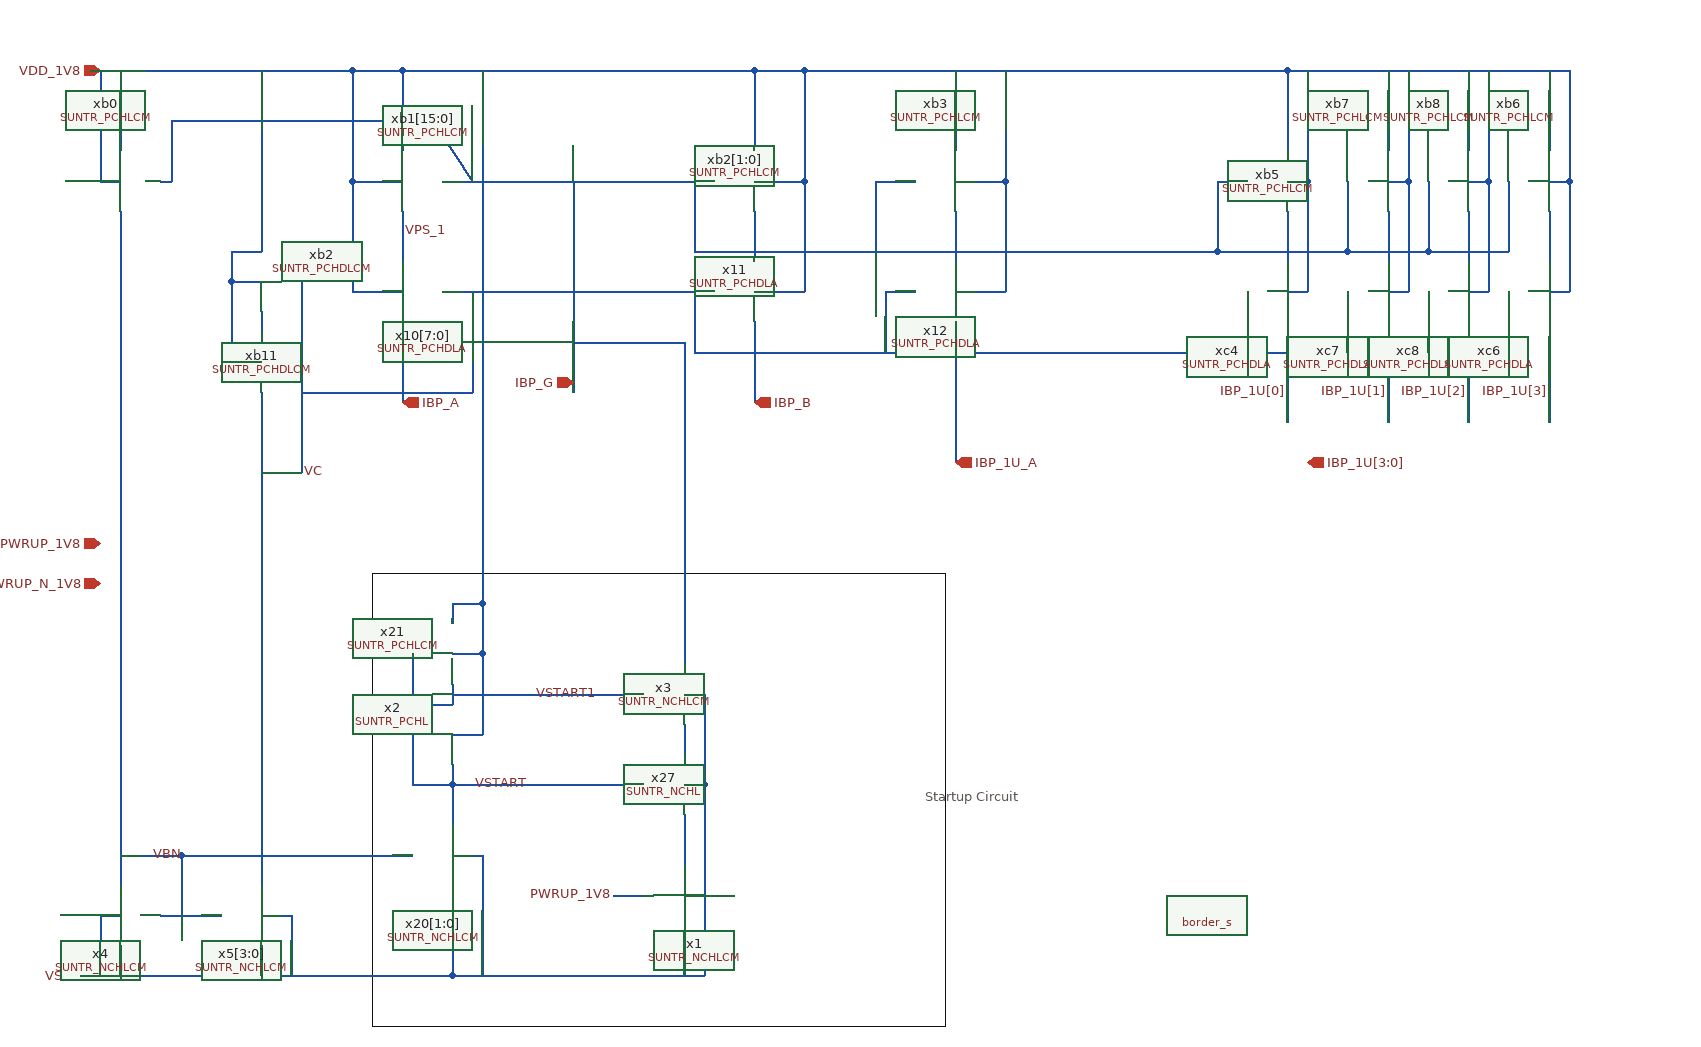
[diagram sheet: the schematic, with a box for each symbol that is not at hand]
v {xschem version=3.1.0 file_version=1.2
}
G {}
K {}
V {}
S {}
E {}
L 3 -320 -340 250 -340 {}
L 3 -320 -340 -320 110 {}
L 3 250 -340 250 110 {}
L 3 -320 110 250 110 {}
T {Startup Circuit} 230 -130 0 1 0.4 0.4 {}
N -340 -730 -290 -730 {
lab=VDD_1V8}
N -340 -760 -340 -730 {
lab=VDD_1V8}
N -340 -840 -340 -760 {
lab=VDD_1V8}
N -340 -840 -290 -840 {
lab=VDD_1V8}
N -290 -840 -290 -760 {
lab=VDD_1V8}
N -290 -840 60 -840 {
lab=VDD_1V8}
N 60 -840 60 -760 {
lab=VDD_1V8}
N -250 -730 20 -730 {
lab=IBP_G}
N -600 -840 -340 -840 {
lab=VDD_1V8}
N -610 60 -370 60 {
lab=VSS}
N 60 -730 110 -730 {
lab=VDD_1V8}
N 110 -840 110 -730 {
lab=VDD_1V8}
N 60 -840 110 -840 {
lab=VDD_1V8}
N 590 -840 590 -760 {
lab=VDD_1V8}
N 110 -840 590 -840 {
lab=VDD_1V8}
N 590 -840 630 -840 {
lab=VDD_1V8}
N 520 -730 550 -730 {
lab=IBP_G}
N 520 -730 520 -660 {
lab=IBP_G}
N 0 -660 520 -660 {
lab=IBP_G}
N 0 -730 0 -660 {
lab=IBP_G}
N 260 -730 310 -730 {
lab=VDD_1V8}
N 310 -840 310 -730 {
lab=VDD_1V8}
N 260 -840 260 -760 {
lab=VDD_1V8}
N 180 -730 220 -730 {
lab=IBP_G}
N 180 -730 180 -660 {
lab=IBP_G}
N -570 -840 -570 -760 {
lab=VDD_1V8}
N -590 -730 -570 -730 {
lab=VDD_1V8}
N -590 -840 -590 -730 {
lab=VDD_1V8}
N -460 -630 -430 -630 {
lab=VDD_1V8}
N -460 -660 -460 -630 {
lab=VDD_1V8}
N -460 -660 -430 -660 {
lab=VDD_1V8}
N -430 -840 -430 -660 {
lab=VDD_1V8}
N -260 -790 -220 -730 {
lab=IBP_G}
N -520 -790 -260 -790 {
lab=IBP_G}
N -520 -790 -520 -730 {
lab=IBP_G}
N -530 -730 -520 -730 {
lab=IBP_G}
N -570 -700 -570 -30 {
lab=VBN}
N -590 -0 -570 -0 {
lab=VSS}
N -590 -0 -590 60 {
lab=VSS}
N -570 30 -570 60 {
lab=VSS}
N -430 30 -430 60 {
lab=VSS}
N -430 0 -400 0 {
lab=VSS}
N -400 0 -400 60 {
lab=VSS}
N -530 0 -470 0 {
lab=VBN}
N -430 -600 -430 -580 {
lab=#net1}
N -430 -450 -430 -30 {
lab=VC}
N -430 -440 -390 -440 {
lab=VC}
N -390 -470 -390 -440 {
lab=VC}
N -390 -550 -390 -470 {
lab=VC}
N -390 -630 -390 -550 {
lab=VC}
N -290 -700 -290 -650 {
lab=VPS_1}
N -340 -620 -290 -620 {
lab=VDD_1V8}
N -340 -730 -340 -620 {
lab=VDD_1V8}
N 60 -700 60 -650 {
lab=#net2}
N 60 -620 110 -620 {
lab=VDD_1V8}
N 110 -730 110 -620 {
lab=VDD_1V8}
N 260 -700 260 -650 {
lab=#net3}
N 260 -620 310 -620 {
lab=VDD_1V8}
N 310 -730 310 -620 {
lab=VDD_1V8}
N 260 -590 260 -570 {
lab=IBP_1U_A}
N 330 -560 390 -560 {
lab=VC}
N 390 -560 550 -560 {
lab=VC}
N 550 -620 550 -560 {
lab=VC}
N -10 -620 20 -620 {
lab=VC}
N -390 -520 -310 -520 {
lab=VC}
N -570 -60 -510 -60 {
lab=VBN}
N -510 -60 -510 0 {
lab=VBN}
N -430 -460 -430 -450 {
lab=VC}
N 590 -700 590 -650 {
lab=#net4}
N 590 -730 610 -730 {
lab=VDD_1V8}
N 610 -840 610 -730 {
lab=VDD_1V8}
N 610 -730 610 -620 {
lab=VDD_1V8}
N 590 -620 610 -620 {
lab=VDD_1V8}
N 690 -840 690 -760 {
lab=VDD_1V8}
N 690 -700 690 -650 {
lab=#net5}
N 690 -730 710 -730 {
lab=VDD_1V8}
N 710 -840 710 -730 {
lab=VDD_1V8}
N 710 -730 710 -620 {
lab=VDD_1V8}
N 690 -620 710 -620 {
lab=VDD_1V8}
N 770 -840 770 -760 {
lab=VDD_1V8}
N 770 -700 770 -650 {
lab=#net6}
N 770 -730 790 -730 {
lab=VDD_1V8}
N 790 -840 790 -730 {
lab=VDD_1V8}
N 790 -730 790 -620 {
lab=VDD_1V8}
N 770 -620 790 -620 {
lab=VDD_1V8}
N 850 -840 850 -760 {
lab=VDD_1V8}
N 850 -700 850 -650 {
lab=#net7}
N 850 -730 870 -730 {
lab=VDD_1V8}
N 870 -840 870 -730 {
lab=VDD_1V8}
N 870 -730 870 -620 {
lab=VDD_1V8}
N 850 -620 870 -620 {
lab=VDD_1V8}
N 630 -840 870 -840 {
lab=VDD_1V8}
N 650 -730 650 -670 {
lab=IBP_G}
N 650 -670 650 -660 {
lab=IBP_G}
N 520 -660 650 -660 {
lab=IBP_G}
N 650 -660 730 -660 {
lab=IBP_G}
N 730 -730 730 -660 {
lab=IBP_G}
N 730 -660 810 -660 {
lab=IBP_G}
N 810 -730 810 -660 {
lab=IBP_G}
N 590 -590 590 -490 {
lab=IBP_1U[0]}
N 690 -590 690 -490 {
lab=IBP_1U[1]}
N 770 -590 770 -490 {
lab=IBP_1U[2]}
N 850 -590 850 -490 {
lab=IBP_1U[3]}
N 550 -560 810 -560 {
lab=VC}
N 810 -620 810 -560 {
lab=VC}
N 730 -620 730 -560 {
lab=VC}
N 650 -620 650 -560 {
lab=VC}
N -230 -620 -10 -620 {
lab=VC}
N 260 -570 260 -450 {
lab=IBP_1U_A}
N -290 -590 -290 -510 {
lab=IBP_A}
N 60 -590 60 -510 {
lab=IBP_B}
N -120 -730 -120 -520 {
lab=IBP_G}
N 10 30 10 60 {
lab=VSS}
N -230 60 -40 60 {
lab=VSS}
N -40 60 10 60 {
lab=VSS}
N -240 -60 -210 -60 {
lab=VSS}
N -210 -60 -210 60 {
lab=VSS}
N -240 -30 -240 60 {
lab=VSS}
N -240 -260 -210 -260 {
lab=VDD_1V8}
N -210 -310 -210 -260 {
lab=VDD_1V8}
N -240 -310 -240 -290 {
lab=VDD_1V8}
N -240 -140 -240 -120 {
lab=VSTART}
N -240 -130 -200 -130 {
lab=VSTART}
N -10 -130 10 -130 {
lab=VSS}
N 10 -130 10 30 {
lab=VSS}
N -10 -190 -10 -160 {
lab=#net8}
N -200 -130 -50 -130 {
lab=VSTART}
N -10 -100 -10 -50 {
lab=#net9}
N -10 -20 10 -20 {
lab=VSS}
N -10 10 -10 60 {
lab=VSS}
N -80 -20 -50 -20 {
lab=PWRUP_1V8}
N -240 -310 -210 -310 {
lab=VDD_1V8}
N -280 -260 -280 -210 {
lab=VSTART1}
N -280 -210 -240 -210 {
lab=VSTART1}
N -240 -230 -240 -210 {
lab=VSTART1}
N -240 -180 -210 -180 {
lab=VDD_1V8}
N -210 -260 -210 -180 {
lab=VDD_1V8}
N -280 -180 -280 -130 {
lab=VSTART}
N -280 -130 -240 -130 {
lab=VSTART}
N -240 -150 -240 -130 {
lab=VSTART}
N -240 -140 -240 -130 {
lab=VSTART}
N -10 -220 10 -220 {
lab=VSS}
N 10 -220 10 -130 {
lab=VSS}
N -10 -260 -10 -250 {
lab=IBP_G}
N -160 -220 -50 -220 {
lab=VSTART1}
N -240 -220 -190 -220 {
lab=VSTART1}
N 0 -620 -0 -560 {
lab=VC}
N -0 -560 330 -560 {
lab=VC}
N -250 -620 -230 -620 {
lab=VC}
N -310 -520 -220 -520 {
lab=VC}
N -220 -620 -220 -520 {
lab=VC}
N -240 -120 -240 -90 {
lab=VSTART}
N -510 -60 -280 -60 {
lab=VBN}
N -240 60 -230 60 {
lab=VSS}
N -370 60 -240 60 {
lab=VSS}
N -210 -840 -210 -310 {
lab=VDD_1V8}
N -120 -570 -10 -570 {
lab=IBP_G}
N -10 -570 -10 -260 {
lab=IBP_G}
N -460 -550 -430 -550 {
lab=VDD_1V8}
N -460 -630 -460 -550 {
lab=VDD_1V8}
N -430 -520 -430 -460 {
lab=VC}
N -190 -220 -160 -220 {
lab=VSTART1}
N 190 -620 220 -620 {
lab=VC}
N 190 -620 190 -560 {
lab=VC}
C {cborder/border_s.sym} 510 0 0 0 {
user="Carsten Wulff"
company="Carsten Wulff Software"}
C {devices/ipin.sym} -590 -840 0 0 {name=p1 lab=VDD_1V8}
C {devices/ipin.sym} -600 60 0 0 {name=p2 lab=VSS}
C {devices/opin.sym} 610 -450 1 0 {name=p8 lab=IBP_1U[3:0]}
C {SUN_TR_SKY130NM/SUNTR_NCHLCM.sym} -530 0 0 1 {name=x4 }
C {SUN_TR_SKY130NM/SUNTR_NCHLCM.sym} -470 0 0 0 {name=x5[3:0] }
C {SUN_TR_SKY130NM/SUNTR_PCHDLA.sym} -250 -620 0 1 {name=x10[7:0] }
C {SUN_TR_SKY130NM/SUNTR_PCHDLA.sym} 20 -620 0 0 {name=x11 }
C {SUN_TR_SKY130NM/SUNTR_PCHDLA.sym} 220 -620 0 0 {name=x12 }
C {SUN_TR_SKY130NM/SUNTR_PCHDLA.sym} 550 -620 0 0 {name=xc4}
C {devices/lab_pin.sym} -390 -440 0 1 {name=l12 sig_type=std_logic lab=VC}
C {devices/lab_pin.sym} -290 -680 0 1 {name=l13 sig_type=std_logic lab=VPS_1}
C {SUN_TR_SKY130NM/SUNTR_PCHLCM.sym} -250 -730 0 1 {name=xb1[15:0] }
C {SUN_TR_SKY130NM/SUNTR_PCHLCM.sym} 20 -730 0 0 {name=xb2[1:0] }
C {SUN_TR_SKY130NM/SUNTR_PCHLCM.sym} 220 -730 0 0 {name=xb3 }
C {SUN_TR_SKY130NM/SUNTR_PCHLCM.sym} 550 -730 0 0 {name=xb5 }
C {SUN_TR_SKY130NM/SUNTR_PCHDLA.sym} 650 -620 0 0 {name=xc7}
C {SUN_TR_SKY130NM/SUNTR_PCHLCM.sym} 650 -730 0 0 {name=xb7 }
C {SUN_TR_SKY130NM/SUNTR_PCHDLA.sym} 730 -620 0 0 {name=xc8}
C {SUN_TR_SKY130NM/SUNTR_PCHLCM.sym} 730 -730 0 0 {name=xb8 }
C {SUN_TR_SKY130NM/SUNTR_PCHDLA.sym} 810 -620 0 0 {name=xc6}
C {SUN_TR_SKY130NM/SUNTR_PCHLCM.sym} 810 -730 0 0 {name=xb6 }
C {devices/lab_wire.sym} 590 -520 1 1 {name=l11 sig_type=std_logic lab=IBP_1U[0]}
C {devices/lab_wire.sym} 690 -520 1 1 {name=l14 sig_type=std_logic lab=IBP_1U[1]}
C {devices/lab_wire.sym} 770 -520 1 1 {name=l15 sig_type=std_logic lab=IBP_1U[2]}
C {devices/lab_wire.sym} 850 -520 1 1 {name=l16 sig_type=std_logic lab=IBP_1U[3]}
C {SUN_TR_SKY130NM/SUNTR_PCHLCM.sym} -530 -730 0 1 {name=xb0 }
C {devices/opin.sym} 260 -450 1 0 {name=p3 lab=IBP_1U_A}
C {devices/opin.sym} -290 -510 1 0 {name=p5 lab=IBP_A}
C {devices/opin.sym} 60 -510 1 0 {name=p6 lab=IBP_B}
C {devices/ipin.sym} -120 -530 3 0 {name=p7 lab=IBP_G}
C {devices/lab_pin.sym} -80 -20 0 0 {name=l8 sig_type=std_logic lab=PWRUP_1V8}
C {SUN_TR_SKY130NM/SUNTR_NCHLCM.sym} -280 -60 0 0 {name=x20[1:0]  }
C {SUN_TR_SKY130NM/SUNTR_PCHLCM.sym} -280 -260 0 0 {name=x21  }
C {SUN_TR_SKY130NM/SUNTR_NCHL.sym} -50 -130 0 0 {name=x27  }
C {devices/lab_wire.sym} -220 -130 0 1 {name=l1 sig_type=std_logic lab=VSTART}
C {SUN_TR_SKY130NM/SUNTR_NCHLCM.sym} -50 -20 0 0 {name=x1  }
C {SUN_TR_SKY130NM/SUNTR_PCHL.sym} -280 -180 0 0 {name=x2  }
C {SUN_TR_SKY130NM/SUNTR_NCHLCM.sym} -50 -220 0 0 {name=x3  }
C {devices/ipin.sym} -590 -370 0 0 {name=p9 lab=PWRUP_1V8}
C {devices/ipin.sym} -590 -330 0 0 {name=p10 lab=PWRUP_N_1V8}
C {SUN_TR_SKY130NM/SUNTR_PCHDLCM.sym} -390 -630 0 1 {name=xb2 }
C {SUN_TR_SKY130NM/SUNTR_PCHDLCM.sym} -390 -550 0 1 {name=xb11}
C {devices/lab_wire.sym} -540 -60 0 1 {name=l2 sig_type=std_logic lab=VBN}
C {devices/lab_wire.sym} -160 -220 0 1 {name=l3 sig_type=std_logic lab=VSTART1}
